VERSION 5.7 ;
  NOWIREEXTENSIONATPIN ON ;
  DIVIDERCHAR "/" ;
  BUSBITCHARS "[]" ;
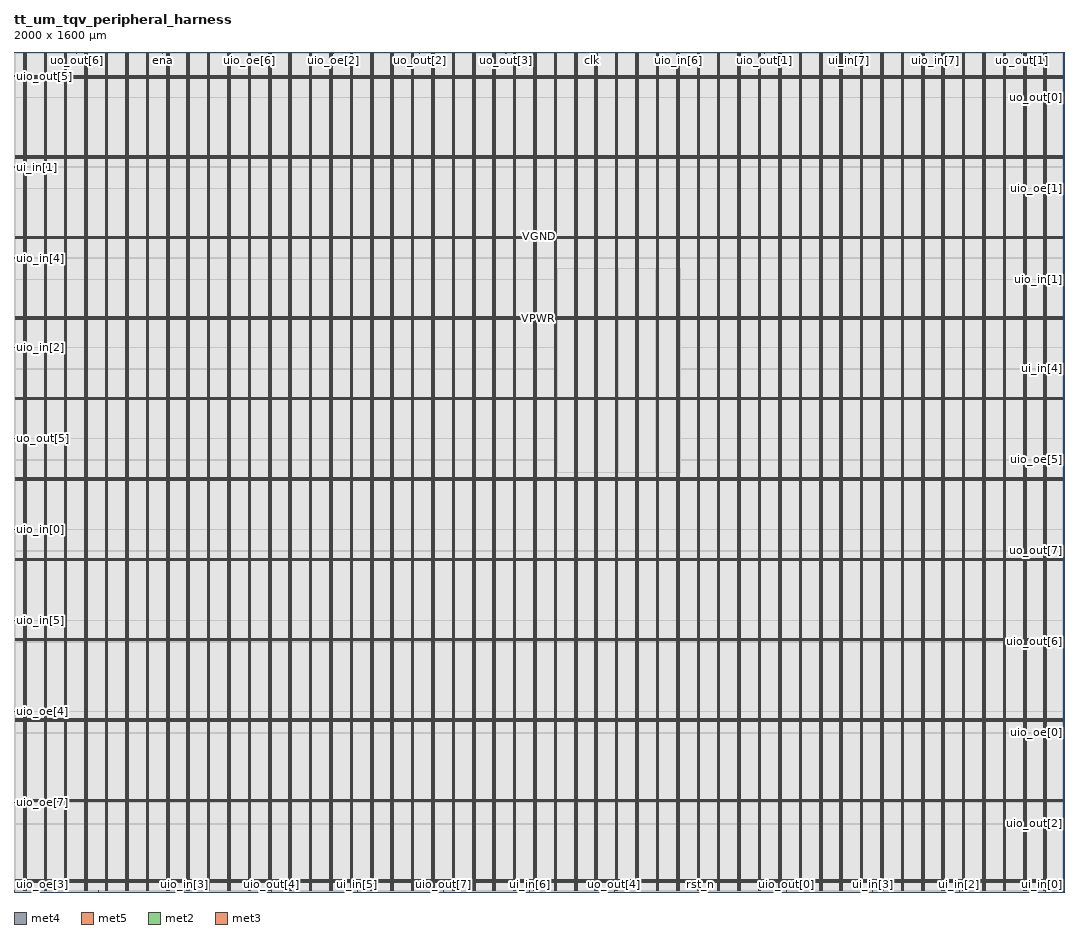
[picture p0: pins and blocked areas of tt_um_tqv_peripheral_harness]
MACRO tt_um_tqv_peripheral_harness
  CLASS BLOCK ;
  FOREIGN tt_um_tqv_peripheral_harness ;
  ORIGIN 0.000 0.000 ;
  SIZE 2000.000 BY 1600.000 ;
  PIN VGND
    DIRECTION INOUT ;
    USE GROUND ;
    PORT
      LAYER met4 ;
        RECT 21.580 2.480 23.180 1596.880 ;
    END
    PORT
      LAYER met4 ;
        RECT 60.450 2.480 62.050 1596.880 ;
    END
    PORT
      LAYER met4 ;
        RECT 99.320 2.480 100.920 1596.880 ;
    END
    PORT
      LAYER met4 ;
        RECT 138.190 2.480 139.790 1596.880 ;
    END
    PORT
      LAYER met4 ;
        RECT 177.060 2.480 178.660 1596.880 ;
    END
    PORT
      LAYER met4 ;
        RECT 215.930 2.480 217.530 1596.880 ;
    END
    PORT
      LAYER met4 ;
        RECT 254.800 2.480 256.400 1596.880 ;
    END
    PORT
      LAYER met4 ;
        RECT 293.670 2.480 295.270 1596.880 ;
    END
    PORT
      LAYER met4 ;
        RECT 332.540 2.480 334.140 1596.880 ;
    END
    PORT
      LAYER met4 ;
        RECT 371.410 2.480 373.010 1596.880 ;
    END
    PORT
      LAYER met4 ;
        RECT 410.280 2.480 411.880 1596.880 ;
    END
    PORT
      LAYER met4 ;
        RECT 449.150 2.480 450.750 1596.880 ;
    END
    PORT
      LAYER met4 ;
        RECT 488.020 2.480 489.620 1596.880 ;
    END
    PORT
      LAYER met4 ;
        RECT 526.890 2.480 528.490 1596.880 ;
    END
    PORT
      LAYER met4 ;
        RECT 565.760 2.480 567.360 1596.880 ;
    END
    PORT
      LAYER met4 ;
        RECT 604.630 2.480 606.230 1596.880 ;
    END
    PORT
      LAYER met4 ;
        RECT 643.500 2.480 645.100 1596.880 ;
    END
    PORT
      LAYER met4 ;
        RECT 682.370 2.480 683.970 1596.880 ;
    END
    PORT
      LAYER met4 ;
        RECT 721.240 2.480 722.840 1596.880 ;
    END
    PORT
      LAYER met4 ;
        RECT 760.110 2.480 761.710 1596.880 ;
    END
    PORT
      LAYER met4 ;
        RECT 798.980 2.480 800.580 1596.880 ;
    END
    PORT
      LAYER met4 ;
        RECT 837.850 2.480 839.450 1596.880 ;
    END
    PORT
      LAYER met4 ;
        RECT 876.720 2.480 878.320 1596.880 ;
    END
    PORT
      LAYER met4 ;
        RECT 915.590 2.480 917.190 1596.880 ;
    END
    PORT
      LAYER met4 ;
        RECT 954.460 2.480 956.060 1596.880 ;
    END
    PORT
      LAYER met4 ;
        RECT 993.330 2.480 994.930 1596.880 ;
    END
    PORT
      LAYER met4 ;
        RECT 1032.200 2.480 1033.800 1596.880 ;
    END
    PORT
      LAYER met4 ;
        RECT 1071.070 2.480 1072.670 1596.880 ;
    END
    PORT
      LAYER met4 ;
        RECT 1109.940 2.480 1111.540 1596.880 ;
    END
    PORT
      LAYER met4 ;
        RECT 1148.810 2.480 1150.410 1596.880 ;
    END
    PORT
      LAYER met4 ;
        RECT 1187.680 2.480 1189.280 1596.880 ;
    END
    PORT
      LAYER met4 ;
        RECT 1226.550 2.480 1228.150 1596.880 ;
    END
    PORT
      LAYER met4 ;
        RECT 1265.420 2.480 1267.020 1596.880 ;
    END
    PORT
      LAYER met4 ;
        RECT 1304.290 2.480 1305.890 1596.880 ;
    END
    PORT
      LAYER met4 ;
        RECT 1343.160 2.480 1344.760 1596.880 ;
    END
    PORT
      LAYER met4 ;
        RECT 1382.030 2.480 1383.630 1596.880 ;
    END
    PORT
      LAYER met4 ;
        RECT 1420.900 2.480 1422.500 1596.880 ;
    END
    PORT
      LAYER met4 ;
        RECT 1459.770 2.480 1461.370 1596.880 ;
    END
    PORT
      LAYER met4 ;
        RECT 1498.640 2.480 1500.240 1596.880 ;
    END
    PORT
      LAYER met4 ;
        RECT 1537.510 2.480 1539.110 1596.880 ;
    END
    PORT
      LAYER met4 ;
        RECT 1576.380 2.480 1577.980 1596.880 ;
    END
    PORT
      LAYER met4 ;
        RECT 1615.250 2.480 1616.850 1596.880 ;
    END
    PORT
      LAYER met4 ;
        RECT 1654.120 2.480 1655.720 1596.880 ;
    END
    PORT
      LAYER met4 ;
        RECT 1692.990 2.480 1694.590 1596.880 ;
    END
    PORT
      LAYER met4 ;
        RECT 1731.860 2.480 1733.460 1596.880 ;
    END
    PORT
      LAYER met4 ;
        RECT 1770.730 2.480 1772.330 1596.880 ;
    END
    PORT
      LAYER met4 ;
        RECT 1809.600 2.480 1811.200 1596.880 ;
    END
    PORT
      LAYER met4 ;
        RECT 1848.470 2.480 1850.070 1596.880 ;
    END
    PORT
      LAYER met4 ;
        RECT 1887.340 2.480 1888.940 1596.880 ;
    END
    PORT
      LAYER met4 ;
        RECT 1926.210 2.480 1927.810 1596.880 ;
    END
    PORT
      LAYER met4 ;
        RECT 1965.080 2.480 1966.680 1596.880 ;
    END
    PORT
      LAYER met5 ;
        RECT 2.520 21.870 1997.100 23.470 ;
    END
    PORT
      LAYER met5 ;
        RECT 2.520 175.050 1997.100 176.650 ;
    END
    PORT
      LAYER met5 ;
        RECT 2.520 328.230 1997.100 329.830 ;
    END
    PORT
      LAYER met5 ;
        RECT 2.520 481.410 1997.100 483.010 ;
    END
    PORT
      LAYER met5 ;
        RECT 2.520 634.590 1997.100 636.190 ;
    END
    PORT
      LAYER met5 ;
        RECT 2.520 787.770 1997.100 789.370 ;
    END
    PORT
      LAYER met5 ;
        RECT 2.520 940.950 1997.100 942.550 ;
    END
    PORT
      LAYER met5 ;
        RECT 2.520 1094.130 1997.100 1095.730 ;
    END
    PORT
      LAYER met5 ;
        RECT 2.520 1247.310 1997.100 1248.910 ;
    END
    PORT
      LAYER met5 ;
        RECT 2.520 1400.490 1997.100 1402.090 ;
    END
    PORT
      LAYER met5 ;
        RECT 2.520 1553.670 1997.100 1555.270 ;
    END
  END VGND
  PIN VPWR
    DIRECTION INOUT ;
    USE POWER ;
    PORT
      LAYER met4 ;
        RECT 18.280 2.480 19.880 1596.880 ;
    END
    PORT
      LAYER met4 ;
        RECT 57.150 2.480 58.750 1596.880 ;
    END
    PORT
      LAYER met4 ;
        RECT 96.020 2.480 97.620 1596.880 ;
    END
    PORT
      LAYER met4 ;
        RECT 134.890 2.480 136.490 1596.880 ;
    END
    PORT
      LAYER met4 ;
        RECT 173.760 2.480 175.360 1596.880 ;
    END
    PORT
      LAYER met4 ;
        RECT 212.630 2.480 214.230 1596.880 ;
    END
    PORT
      LAYER met4 ;
        RECT 251.500 2.480 253.100 1596.880 ;
    END
    PORT
      LAYER met4 ;
        RECT 290.370 2.480 291.970 1596.880 ;
    END
    PORT
      LAYER met4 ;
        RECT 329.240 2.480 330.840 1596.880 ;
    END
    PORT
      LAYER met4 ;
        RECT 368.110 2.480 369.710 1596.880 ;
    END
    PORT
      LAYER met4 ;
        RECT 406.980 2.480 408.580 1596.880 ;
    END
    PORT
      LAYER met4 ;
        RECT 445.850 2.480 447.450 1596.880 ;
    END
    PORT
      LAYER met4 ;
        RECT 484.720 2.480 486.320 1596.880 ;
    END
    PORT
      LAYER met4 ;
        RECT 523.590 2.480 525.190 1596.880 ;
    END
    PORT
      LAYER met4 ;
        RECT 562.460 2.480 564.060 1596.880 ;
    END
    PORT
      LAYER met4 ;
        RECT 601.330 2.480 602.930 1596.880 ;
    END
    PORT
      LAYER met4 ;
        RECT 640.200 2.480 641.800 1596.880 ;
    END
    PORT
      LAYER met4 ;
        RECT 679.070 2.480 680.670 1596.880 ;
    END
    PORT
      LAYER met4 ;
        RECT 717.940 2.480 719.540 1596.880 ;
    END
    PORT
      LAYER met4 ;
        RECT 756.810 2.480 758.410 1596.880 ;
    END
    PORT
      LAYER met4 ;
        RECT 795.680 2.480 797.280 1596.880 ;
    END
    PORT
      LAYER met4 ;
        RECT 834.550 2.480 836.150 1596.880 ;
    END
    PORT
      LAYER met4 ;
        RECT 873.420 2.480 875.020 1596.880 ;
    END
    PORT
      LAYER met4 ;
        RECT 912.290 2.480 913.890 1596.880 ;
    END
    PORT
      LAYER met4 ;
        RECT 951.160 2.480 952.760 1596.880 ;
    END
    PORT
      LAYER met4 ;
        RECT 990.030 2.480 991.630 1596.880 ;
    END
    PORT
      LAYER met4 ;
        RECT 1028.900 2.480 1030.500 1596.880 ;
    END
    PORT
      LAYER met4 ;
        RECT 1067.770 2.480 1069.370 1596.880 ;
    END
    PORT
      LAYER met4 ;
        RECT 1106.640 2.480 1108.240 1596.880 ;
    END
    PORT
      LAYER met4 ;
        RECT 1145.510 2.480 1147.110 1596.880 ;
    END
    PORT
      LAYER met4 ;
        RECT 1184.380 2.480 1185.980 1596.880 ;
    END
    PORT
      LAYER met4 ;
        RECT 1223.250 2.480 1224.850 1596.880 ;
    END
    PORT
      LAYER met4 ;
        RECT 1262.120 2.480 1263.720 1596.880 ;
    END
    PORT
      LAYER met4 ;
        RECT 1300.990 2.480 1302.590 1596.880 ;
    END
    PORT
      LAYER met4 ;
        RECT 1339.860 2.480 1341.460 1596.880 ;
    END
    PORT
      LAYER met4 ;
        RECT 1378.730 2.480 1380.330 1596.880 ;
    END
    PORT
      LAYER met4 ;
        RECT 1417.600 2.480 1419.200 1596.880 ;
    END
    PORT
      LAYER met4 ;
        RECT 1456.470 2.480 1458.070 1596.880 ;
    END
    PORT
      LAYER met4 ;
        RECT 1495.340 2.480 1496.940 1596.880 ;
    END
    PORT
      LAYER met4 ;
        RECT 1534.210 2.480 1535.810 1596.880 ;
    END
    PORT
      LAYER met4 ;
        RECT 1573.080 2.480 1574.680 1596.880 ;
    END
    PORT
      LAYER met4 ;
        RECT 1611.950 2.480 1613.550 1596.880 ;
    END
    PORT
      LAYER met4 ;
        RECT 1650.820 2.480 1652.420 1596.880 ;
    END
    PORT
      LAYER met4 ;
        RECT 1689.690 2.480 1691.290 1596.880 ;
    END
    PORT
      LAYER met4 ;
        RECT 1728.560 2.480 1730.160 1596.880 ;
    END
    PORT
      LAYER met4 ;
        RECT 1767.430 2.480 1769.030 1596.880 ;
    END
    PORT
      LAYER met4 ;
        RECT 1806.300 2.480 1807.900 1596.880 ;
    END
    PORT
      LAYER met4 ;
        RECT 1845.170 2.480 1846.770 1596.880 ;
    END
    PORT
      LAYER met4 ;
        RECT 1884.040 2.480 1885.640 1596.880 ;
    END
    PORT
      LAYER met4 ;
        RECT 1922.910 2.480 1924.510 1596.880 ;
    END
    PORT
      LAYER met4 ;
        RECT 1961.780 2.480 1963.380 1596.880 ;
    END
    PORT
      LAYER met5 ;
        RECT 2.520 18.570 1997.100 20.170 ;
    END
    PORT
      LAYER met5 ;
        RECT 2.520 171.750 1997.100 173.350 ;
    END
    PORT
      LAYER met5 ;
        RECT 2.520 324.930 1997.100 326.530 ;
    END
    PORT
      LAYER met5 ;
        RECT 2.520 478.110 1997.100 479.710 ;
    END
    PORT
      LAYER met5 ;
        RECT 2.520 631.290 1997.100 632.890 ;
    END
    PORT
      LAYER met5 ;
        RECT 2.520 784.470 1997.100 786.070 ;
    END
    PORT
      LAYER met5 ;
        RECT 2.520 937.650 1997.100 939.250 ;
    END
    PORT
      LAYER met5 ;
        RECT 2.520 1090.830 1997.100 1092.430 ;
    END
    PORT
      LAYER met5 ;
        RECT 2.520 1244.010 1997.100 1245.610 ;
    END
    PORT
      LAYER met5 ;
        RECT 2.520 1397.190 1997.100 1398.790 ;
    END
    PORT
      LAYER met5 ;
        RECT 2.520 1550.370 1997.100 1551.970 ;
    END
  END VPWR
  PIN clk
    DIRECTION INPUT ;
    USE SIGNAL ;
    ANTENNAGATEAREA 0.852000 ;
    PORT
      LAYER met2 ;
        RECT 1101.330 1598.000 1101.610 1600.000 ;
    END
  END clk
  PIN ena
    DIRECTION INPUT ;
    USE SIGNAL ;
    PORT
      LAYER met2 ;
        RECT 283.450 1598.000 283.730 1600.000 ;
    END
  END ena
  PIN rst_n
    DIRECTION INPUT ;
    USE SIGNAL ;
    ANTENNAGATEAREA 0.426000 ;
    PORT
      LAYER met2 ;
        RECT 1307.410 0.000 1307.690 2.000 ;
    END
  END rst_n
  PIN ui_in[0]
    DIRECTION INPUT ;
    USE SIGNAL ;
    ANTENNAGATEAREA 0.852000 ;
    PORT
      LAYER met2 ;
        RECT 1964.290 0.000 1964.570 2.000 ;
    END
  END ui_in[0]
  PIN ui_in[1]
    DIRECTION INPUT ;
    USE SIGNAL ;
    ANTENNAGATEAREA 0.742500 ;
    PORT
      LAYER met3 ;
        RECT 0.000 1380.440 2.000 1381.040 ;
    END
  END ui_in[1]
  PIN ui_in[2]
    DIRECTION INPUT ;
    USE SIGNAL ;
    ANTENNAGATEAREA 0.742500 ;
    PORT
      LAYER met2 ;
        RECT 1800.070 0.000 1800.350 2.000 ;
    END
  END ui_in[2]
  PIN ui_in[3]
    DIRECTION INPUT ;
    USE SIGNAL ;
    ANTENNAGATEAREA 0.742500 ;
    PORT
      LAYER met2 ;
        RECT 1635.850 0.000 1636.130 2.000 ;
    END
  END ui_in[3]
  PIN ui_in[4]
    DIRECTION INPUT ;
    USE SIGNAL ;
    ANTENNAGATEAREA 0.426000 ;
    PORT
      LAYER met3 ;
        RECT 1998.000 996.240 2000.000 996.840 ;
    END
  END ui_in[4]
  PIN ui_in[5]
    DIRECTION INPUT ;
    USE SIGNAL ;
    ANTENNAGATEAREA 0.742500 ;
    PORT
      LAYER met2 ;
        RECT 653.750 0.000 654.030 2.000 ;
    END
  END ui_in[5]
  PIN ui_in[6]
    DIRECTION INPUT ;
    USE SIGNAL ;
    ANTENNAGATEAREA 0.247500 ;
    PORT
      LAYER met2 ;
        RECT 982.190 0.000 982.470 2.000 ;
    END
  END ui_in[6]
  PIN ui_in[7]
    DIRECTION INPUT ;
    USE SIGNAL ;
    ANTENNAGATEAREA 0.159000 ;
    PORT
      LAYER met2 ;
        RECT 1590.770 1598.000 1591.050 1600.000 ;
    END
  END ui_in[7]
  PIN uio_in[0]
    DIRECTION INPUT ;
    USE SIGNAL ;
    PORT
      LAYER met3 ;
        RECT 0.000 690.240 2.000 690.840 ;
    END
  END uio_in[0]
  PIN uio_in[1]
    DIRECTION INPUT ;
    USE SIGNAL ;
    PORT
      LAYER met3 ;
        RECT 1998.000 1166.240 2000.000 1166.840 ;
    END
  END uio_in[1]
  PIN uio_in[2]
    DIRECTION INPUT ;
    USE SIGNAL ;
    PORT
      LAYER met3 ;
        RECT 0.000 1037.040 2.000 1037.640 ;
    END
  END uio_in[2]
  PIN uio_in[3]
    DIRECTION INPUT ;
    USE SIGNAL ;
    PORT
      LAYER met2 ;
        RECT 325.310 0.000 325.590 2.000 ;
    END
  END uio_in[3]
  PIN uio_in[4]
    DIRECTION INPUT ;
    USE SIGNAL ;
    ANTENNAGATEAREA 0.495000 ;
    PORT
      LAYER met3 ;
        RECT 0.000 1207.040 2.000 1207.640 ;
    END
  END uio_in[4]
  PIN uio_in[5]
    DIRECTION INPUT ;
    USE SIGNAL ;
    ANTENNAGATEAREA 0.852000 ;
    PORT
      LAYER met3 ;
        RECT 0.000 516.840 2.000 517.440 ;
    END
  END uio_in[5]
  PIN uio_in[6]
    DIRECTION INPUT ;
    USE SIGNAL ;
    ANTENNAGATEAREA 0.196500 ;
    PORT
      LAYER met2 ;
        RECT 1265.550 1598.000 1265.830 1600.000 ;
    END
  END uio_in[6]
  PIN uio_in[7]
    DIRECTION INPUT ;
    USE SIGNAL ;
    PORT
      LAYER met2 ;
        RECT 1754.990 1598.000 1755.270 1600.000 ;
    END
  END uio_in[7]
  PIN uio_oe[0]
    DIRECTION OUTPUT TRISTATE ;
    USE SIGNAL ;
    PORT
      LAYER met3 ;
        RECT 1998.000 302.640 2000.000 303.240 ;
    END
  END uio_oe[0]
  PIN uio_oe[1]
    DIRECTION OUTPUT TRISTATE ;
    USE SIGNAL ;
    PORT
      LAYER met3 ;
        RECT 1998.000 1339.640 2000.000 1340.240 ;
    END
  END uio_oe[1]
  PIN uio_oe[2]
    DIRECTION OUTPUT TRISTATE ;
    USE SIGNAL ;
    PORT
      LAYER met2 ;
        RECT 608.670 1598.000 608.950 1600.000 ;
    END
  END uio_oe[2]
  PIN uio_oe[3]
    DIRECTION OUTPUT TRISTATE ;
    USE SIGNAL ;
    PORT
      LAYER met2 ;
        RECT 0.090 0.000 0.370 2.000 ;
    END
  END uio_oe[3]
  PIN uio_oe[4]
    DIRECTION OUTPUT TRISTATE ;
    USE SIGNAL ;
    PORT
      LAYER met3 ;
        RECT 0.000 343.440 2.000 344.040 ;
    END
  END uio_oe[4]
  PIN uio_oe[5]
    DIRECTION OUTPUT TRISTATE ;
    USE SIGNAL ;
    PORT
      LAYER met3 ;
        RECT 1998.000 822.840 2000.000 823.440 ;
    END
  END uio_oe[5]
  PIN uio_oe[6]
    DIRECTION OUTPUT TRISTATE ;
    USE SIGNAL ;
    PORT
      LAYER met2 ;
        RECT 447.670 1598.000 447.950 1600.000 ;
    END
  END uio_oe[6]
  PIN uio_oe[7]
    DIRECTION OUTPUT TRISTATE ;
    USE SIGNAL ;
    PORT
      LAYER met3 ;
        RECT 0.000 170.040 2.000 170.640 ;
    END
  END uio_oe[7]
  PIN uio_out[0]
    DIRECTION OUTPUT TRISTATE ;
    USE SIGNAL ;
    PORT
      LAYER met2 ;
        RECT 1471.630 0.000 1471.910 2.000 ;
    END
  END uio_out[0]
  PIN uio_out[1]
    DIRECTION OUTPUT TRISTATE ;
    USE SIGNAL ;
    ANTENNADIFFAREA 0.795200 ;
    PORT
      LAYER met2 ;
        RECT 1429.770 1598.000 1430.050 1600.000 ;
    END
  END uio_out[1]
  PIN uio_out[2]
    DIRECTION OUTPUT TRISTATE ;
    USE SIGNAL ;
    PORT
      LAYER met3 ;
        RECT 1998.000 129.240 2000.000 129.840 ;
    END
  END uio_out[2]
  PIN uio_out[3]
    DIRECTION OUTPUT TRISTATE ;
    USE SIGNAL ;
    ANTENNADIFFAREA 0.445500 ;
    PORT
      LAYER met2 ;
        RECT 161.090 0.000 161.370 2.000 ;
    END
  END uio_out[3]
  PIN uio_out[4]
    DIRECTION OUTPUT TRISTATE ;
    USE SIGNAL ;
    PORT
      LAYER met2 ;
        RECT 489.530 0.000 489.810 2.000 ;
    END
  END uio_out[4]
  PIN uio_out[5]
    DIRECTION OUTPUT TRISTATE ;
    USE SIGNAL ;
    PORT
      LAYER met3 ;
        RECT 0.000 1553.840 2.000 1554.440 ;
    END
  END uio_out[5]
  PIN uio_out[6]
    DIRECTION OUTPUT TRISTATE ;
    USE SIGNAL ;
    PORT
      LAYER met3 ;
        RECT 1998.000 476.040 2000.000 476.640 ;
    END
  END uio_out[6]
  PIN uio_out[7]
    DIRECTION OUTPUT TRISTATE ;
    USE SIGNAL ;
    PORT
      LAYER met2 ;
        RECT 817.970 0.000 818.250 2.000 ;
    END
  END uio_out[7]
  PIN uo_out[0]
    DIRECTION OUTPUT TRISTATE ;
    USE SIGNAL ;
    ANTENNADIFFAREA 0.795200 ;
    PORT
      LAYER met3 ;
        RECT 1998.000 1513.040 2000.000 1513.640 ;
    END
  END uo_out[0]
  PIN uo_out[1]
    DIRECTION OUTPUT TRISTATE ;
    USE SIGNAL ;
    ANTENNADIFFAREA 0.795200 ;
    PORT
      LAYER met2 ;
        RECT 1919.210 1598.000 1919.490 1600.000 ;
    END
  END uo_out[1]
  PIN uo_out[2]
    DIRECTION OUTPUT TRISTATE ;
    USE SIGNAL ;
    ANTENNADIFFAREA 0.795200 ;
    PORT
      LAYER met2 ;
        RECT 772.890 1598.000 773.170 1600.000 ;
    END
  END uo_out[2]
  PIN uo_out[3]
    DIRECTION OUTPUT TRISTATE ;
    USE SIGNAL ;
    ANTENNADIFFAREA 0.795200 ;
    PORT
      LAYER met2 ;
        RECT 937.110 1598.000 937.390 1600.000 ;
    END
  END uo_out[3]
  PIN uo_out[4]
    DIRECTION OUTPUT TRISTATE ;
    USE SIGNAL ;
    ANTENNADIFFAREA 0.445500 ;
    PORT
      LAYER met2 ;
        RECT 1143.190 0.000 1143.470 2.000 ;
    END
  END uo_out[4]
  PIN uo_out[5]
    DIRECTION OUTPUT TRISTATE ;
    USE SIGNAL ;
    ANTENNADIFFAREA 0.445500 ;
    PORT
      LAYER met3 ;
        RECT 0.000 863.640 2.000 864.240 ;
    END
  END uo_out[5]
  PIN uo_out[6]
    DIRECTION OUTPUT TRISTATE ;
    USE SIGNAL ;
    ANTENNADIFFAREA 0.795200 ;
    PORT
      LAYER met2 ;
        RECT 119.230 1598.000 119.510 1600.000 ;
    END
  END uo_out[6]
  PIN uo_out[7]
    DIRECTION OUTPUT TRISTATE ;
    USE SIGNAL ;
    ANTENNADIFFAREA 0.795200 ;
    PORT
      LAYER met3 ;
        RECT 1998.000 649.440 2000.000 650.040 ;
    END
  END uo_out[7]
  OBS
      LAYER li1 ;
        RECT 2.760 2.635 1996.860 1596.725 ;
      LAYER met1 ;
        RECT 0.070 2.480 1996.860 1596.880 ;
      LAYER met2 ;
        RECT 0.100 1597.720 118.950 1598.000 ;
        RECT 119.790 1597.720 283.170 1598.000 ;
        RECT 284.010 1597.720 447.390 1598.000 ;
        RECT 448.230 1597.720 608.390 1598.000 ;
        RECT 609.230 1597.720 772.610 1598.000 ;
        RECT 773.450 1597.720 936.830 1598.000 ;
        RECT 937.670 1597.720 1101.050 1598.000 ;
        RECT 1101.890 1597.720 1265.270 1598.000 ;
        RECT 1266.110 1597.720 1429.490 1598.000 ;
        RECT 1430.330 1597.720 1590.490 1598.000 ;
        RECT 1591.330 1597.720 1754.710 1598.000 ;
        RECT 1755.550 1597.720 1918.930 1598.000 ;
        RECT 1919.770 1597.720 1995.390 1598.000 ;
        RECT 0.100 2.280 1995.390 1597.720 ;
        RECT 0.650 1.630 160.810 2.280 ;
        RECT 161.650 1.630 325.030 2.280 ;
        RECT 325.870 1.630 489.250 2.280 ;
        RECT 490.090 1.630 653.470 2.280 ;
        RECT 654.310 1.630 817.690 2.280 ;
        RECT 818.530 1.630 981.910 2.280 ;
        RECT 982.750 1.630 1142.910 2.280 ;
        RECT 1143.750 1.630 1307.130 2.280 ;
        RECT 1307.970 1.630 1471.350 2.280 ;
        RECT 1472.190 1.630 1635.570 2.280 ;
        RECT 1636.410 1.630 1799.790 2.280 ;
        RECT 1800.630 1.630 1964.010 2.280 ;
        RECT 1964.850 1.630 1995.390 2.280 ;
      LAYER met3 ;
        RECT 2.000 1554.840 1998.000 1596.805 ;
        RECT 2.400 1553.440 1998.000 1554.840 ;
        RECT 2.000 1514.040 1998.000 1553.440 ;
        RECT 2.000 1512.640 1997.600 1514.040 ;
        RECT 2.000 1381.440 1998.000 1512.640 ;
        RECT 2.400 1380.040 1998.000 1381.440 ;
        RECT 2.000 1340.640 1998.000 1380.040 ;
        RECT 2.000 1339.240 1997.600 1340.640 ;
        RECT 2.000 1208.040 1998.000 1339.240 ;
        RECT 2.400 1206.640 1998.000 1208.040 ;
        RECT 2.000 1167.240 1998.000 1206.640 ;
        RECT 2.000 1165.840 1997.600 1167.240 ;
        RECT 2.000 1038.040 1998.000 1165.840 ;
        RECT 2.400 1036.640 1998.000 1038.040 ;
        RECT 2.000 997.240 1998.000 1036.640 ;
        RECT 2.000 995.840 1997.600 997.240 ;
        RECT 2.000 864.640 1998.000 995.840 ;
        RECT 2.400 863.240 1998.000 864.640 ;
        RECT 2.000 823.840 1998.000 863.240 ;
        RECT 2.000 822.440 1997.600 823.840 ;
        RECT 2.000 691.240 1998.000 822.440 ;
        RECT 2.400 689.840 1998.000 691.240 ;
        RECT 2.000 650.440 1998.000 689.840 ;
        RECT 2.000 649.040 1997.600 650.440 ;
        RECT 2.000 517.840 1998.000 649.040 ;
        RECT 2.400 516.440 1998.000 517.840 ;
        RECT 2.000 477.040 1998.000 516.440 ;
        RECT 2.000 475.640 1997.600 477.040 ;
        RECT 2.000 344.440 1998.000 475.640 ;
        RECT 2.400 343.040 1998.000 344.440 ;
        RECT 2.000 303.640 1998.000 343.040 ;
        RECT 2.000 302.240 1997.600 303.640 ;
        RECT 2.000 171.040 1998.000 302.240 ;
        RECT 2.400 169.640 1998.000 171.040 ;
        RECT 2.000 130.240 1998.000 169.640 ;
        RECT 2.000 128.840 1997.600 130.240 ;
        RECT 2.000 2.555 1998.000 128.840 ;
      LAYER met4 ;
        RECT 1034.375 799.855 1067.370 1187.105 ;
        RECT 1069.770 799.855 1070.670 1187.105 ;
        RECT 1073.070 799.855 1106.240 1187.105 ;
        RECT 1108.640 799.855 1109.540 1187.105 ;
        RECT 1111.940 799.855 1145.110 1187.105 ;
        RECT 1147.510 799.855 1148.410 1187.105 ;
        RECT 1150.810 799.855 1183.980 1187.105 ;
        RECT 1186.380 799.855 1187.280 1187.105 ;
        RECT 1189.680 799.855 1222.850 1187.105 ;
        RECT 1225.250 799.855 1226.150 1187.105 ;
        RECT 1228.550 799.855 1261.720 1187.105 ;
        RECT 1264.120 799.855 1265.020 1187.105 ;
        RECT 1267.420 799.855 1269.305 1187.105 ;
  END
END tt_um_tqv_peripheral_harness
END LIBRARY

